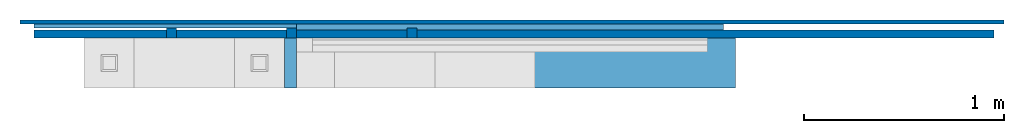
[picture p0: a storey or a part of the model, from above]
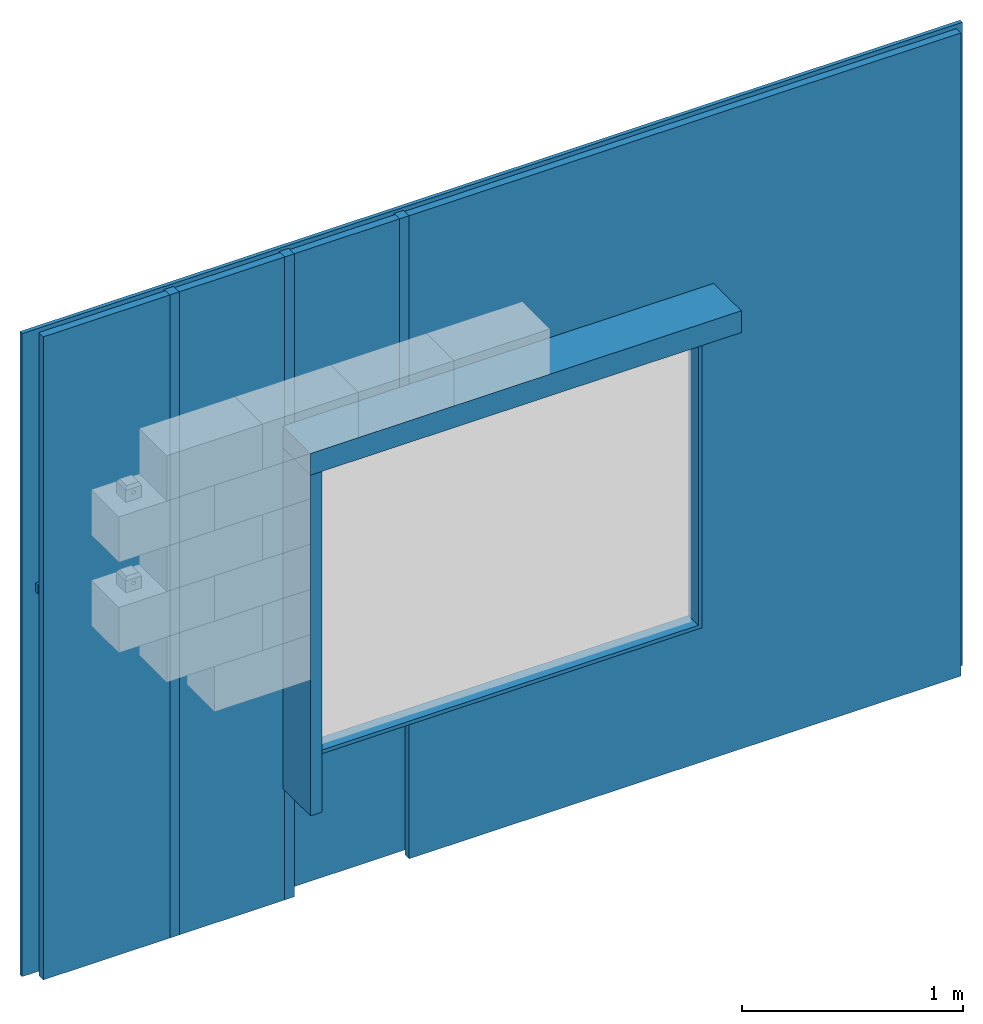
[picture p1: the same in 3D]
Properties of the parts of a building model (IFC4)

# File
Description: ViewDefinition [ReferenceView_V1.2], RevitIdentifiers [ContentGUID: 220a4939-3971-4e9b-89b3-fe80d098a815, VersionGUID: d7252125-2e6f-444e-b0fa-fdf360d79000, NumberOfSaves: 84], CoordinateReference [CoordinateBase: Internal Origin, ProjectSite: Internal], ExchangeRequirement [Architecture]
File name: 3dv__Detail__15__209, WS25.ifc
Time: 2025-12-19T14:07:34+01:00
Written by: ODA SDAI 25.12
Made in: Autodesk - Revit 26.3.0.37 (ENU) - 26.4.1.0

# IfcSite, Default
RefLatitude: 50, 59, 55, 811462; RefLongitude: 6, 47, 53, 300743; RefElevation: 0 cm

# IfcBuildingStorey (2)
Name | LongName | Elevation (cm)
L00__ABOVE Slab | L00__ABOVE Slab | -23.7
L01__ABOVE Slab | L01__ABOVE Slab | 269.3

# IfcBeam: Structural Framing : sfr__WOOD__Rectangular__sf : 10 x 18 cm (15)
In: L01__ABOVE Slab
Type - PredefinedType: JOIST; Material: _STRUCTURE__Wood Solid
Classification: S 1.3 Beams (Uniformat)

# IfcBeam: Structural Framing : wll__PARAPET CAP__Metal__sf : Wall Coping w/ H 50mm Nose, Stamped AL Profile
In: L01__ABOVE Slab
Type - PredefinedType: BEAM; Material: _SILL__Sill__Metal
Classification: A 4.4.2 Flashing-uri tabla ambutisata (Uniformat)

# IfcBuildingElementPart (5)
In: L01__ABOVE Slab
Name | Material
_FLR LAYERS__WP Membrane__EPDM | _FLR LAYERS__WP Membrane__EPDM
2 x _FND LAYERS__Insulation__Foam Glass__Glapor PG UMB1 | _FND LAYERS__Insulation__Foam Glass__Glapor PG UMB1
_FLR LAYERS__Fleece__Glapor Connect | _FLR LAYERS__Fleece__Glapor Connect
_FLR LAYERS__Screed__Dry__Cemwood 1000 | _FLR LAYERS__Screed__Dry__Cemwood 1000

# IfcElementAssembly, Structural Beam Systems : Structural Beam System : Structural Beam System 1
In: L01__ABOVE Slab
PredefinedType: BEAM_GRID

# IfcOpeningElement (2)
In: L00__ABOVE Slab
PredefinedType: OPENING

# IfcSlab: Floors : Floor : flr__EXT ENCLOSURE__5cm__TriqBriq, TR.1
In: L01__ABOVE Slab
Type - PredefinedType: FLOOR
Classification: A 3.3.4 Non-circulating, technical systems (maintenance traffic and equipment loads) (Uniformat)

# IfcSlab: Floors : Floor : flr__EXT ENCLOSURE__WP, Foam Glass 20.4cm__Under Bsmt Slab, TriqBriq, TR.2
In: L01__ABOVE Slab
Type - PredefinedType: FLOOR
Classification: A 3.3.4 Non-circulating, technical systems (maintenance traffic and equipment loads) (Uniformat)

# IfcWall (12)
Name (Parts :...) | In | Material
5 x  Part | L00__ABOVE Slab | _STRUCTURE__Wood Solid
4 x  Part | L00__ABOVE Slab | _FCD LAYERS__Insulation__Wood-fiber__Gutex Multitherm
 Part | L00__ABOVE Slab | _FCD VENT FINISH__Wood__Thermory C34
2 x  Part | L01__ABOVE Slab | _STRUCTURE__Wood Solid

# IfcWall: Columns : wll_s__TIMBER BLOCK__Triqbriq, Full Width__wp : WS25 (19)
Type - PredefinedType: SOLIDWALL; Material: Miscellaneous__Timber Block__Triqbriq, Y
Classification: A 1.0.1 Load-bearing modular timber frame construction (Uniformat)
Name (Columns : wll_s__TIMBER BLOCK__Triqbriq, Full Width__wp :...) | In
11 x  WS25 | L00__ABOVE Slab
8 x  WS25 | L01__ABOVE Slab

# IfcWall: Columns : wll_s__TIMBER BLOCK__Triqbriq, Half Width__wp : WS25 (2)
In: L00__ABOVE Slab
Type - PredefinedType: SOLIDWALL; Material: Miscellaneous__Timber Block__Triqbriq, Y
Classification: A 1.0.1 Load-bearing modular timber frame construction (Uniformat)

# IfcWall: Structural Framing : wll_s__LINTEL__Triqbriq, Rectangular__wp : Wood (2)
In: L00__ABOVE Slab
Type - PredefinedType: SOLIDWALL; Material: _STRUCTURE__Wood Solid
Classification: A 1.0.3 Modular Wood Frame Wall Add-on Components (Uniformat)

# IfcWindow: Windows : wdw_s__PANEL__Fixed__wp : Glazed
In: L00__ABOVE Slab
Type - PredefinedType: WINDOW; Material: _WINDOW__Glazing
OverallHeight: 7 cm; OverallWidth: 197 cm

# IfcWindow: Windows : wdw_s__PROFILE__Frame__wp : Wood (2)
In: L00__ABOVE Slab
Type - PredefinedType: WINDOW; Material: _WINDOW__Profile__Wood
OverallHeight: 28.3557 cm; OverallWidth: 8 cm
